VERSION 5.7 ;
BUSBITCHARS "[]" ;
DIVIDERCHAR "/" ;

UNITS
  DATABASE MICRONS 2000 ;
END UNITS

# Site definition
SITE core7
  CLASS CORE ;
  SIZE 0.38 BY 2.8 ;
END core7

# Metal layers for routing
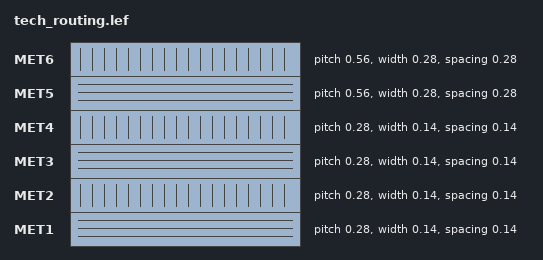
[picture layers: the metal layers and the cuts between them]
LAYER MET1
  TYPE ROUTING ;
  DIRECTION HORIZONTAL ;
  PITCH 0.28 ;
  WIDTH 0.14 ;
  SPACING 0.14 ;
  RESISTANCE RPERSQ 0.08 ;
  CAPACITANCE CPERSQDIST 0.00015 ;
END MET1

LAYER MET2
  TYPE ROUTING ;
  DIRECTION VERTICAL ;
  PITCH 0.28 ;
  WIDTH 0.14 ;
  SPACING 0.14 ;
  RESISTANCE RPERSQ 0.08 ;
  CAPACITANCE CPERSQDIST 0.00015 ;
END MET2

LAYER MET3
  TYPE ROUTING ;
  DIRECTION HORIZONTAL ;
  PITCH 0.28 ;
  WIDTH 0.14 ;
  SPACING 0.14 ;
  RESISTANCE RPERSQ 0.08 ;
  CAPACITANCE CPERSQDIST 0.00015 ;
END MET3

LAYER MET4
  TYPE ROUTING ;
  DIRECTION VERTICAL ;
  PITCH 0.28 ;
  WIDTH 0.14 ;
  SPACING 0.14 ;
  RESISTANCE RPERSQ 0.08 ;
  CAPACITANCE CPERSQDIST 0.00015 ;
END MET4

LAYER MET5
  TYPE ROUTING ;
  DIRECTION HORIZONTAL ;
  PITCH 0.56 ;
  WIDTH 0.28 ;
  SPACING 0.28 ;
  RESISTANCE RPERSQ 0.04 ;
  CAPACITANCE CPERSQDIST 0.00012 ;
END MET5

LAYER MET6
  TYPE ROUTING ;
  DIRECTION VERTICAL ;
  PITCH 0.56 ;
  WIDTH 0.28 ;
  SPACING 0.28 ;
  RESISTANCE RPERSQ 0.04 ;
  CAPACITANCE CPERSQDIST 0.00012 ;
END MET6

# Via definitions
VIA VIA12 DEFAULT
  LAYER MET1 ;
    RECT -0.07 -0.07 0.07 0.07 ;
  LAYER VIA1 ;
    RECT -0.065 -0.065 0.065 0.065 ;
  LAYER MET2 ;
    RECT -0.07 -0.07 0.07 0.07 ;
END VIA12

VIA VIA23 DEFAULT
  LAYER MET2 ;
    RECT -0.07 -0.07 0.07 0.07 ;
  LAYER VIA2 ;
    RECT -0.065 -0.065 0.065 0.065 ;
  LAYER MET3 ;
    RECT -0.07 -0.07 0.07 0.07 ;
END VIA23

VIA VIA34 DEFAULT
  LAYER MET3 ;
    RECT -0.07 -0.07 0.07 0.07 ;
  LAYER VIA3 ;
    RECT -0.065 -0.065 0.065 0.065 ;
  LAYER MET4 ;
    RECT -0.07 -0.07 0.07 0.07 ;
END VIA34

VIA VIA45 DEFAULT
  LAYER MET4 ;
    RECT -0.14 -0.14 0.14 0.14 ;
  LAYER VIA4 ;
    RECT -0.13 -0.13 0.13 0.13 ;
  LAYER MET5 ;
    RECT -0.14 -0.14 0.14 0.14 ;
END VIA45

VIA VIA56 DEFAULT
  LAYER MET5 ;
    RECT -0.14 -0.14 0.14 0.14 ;
  LAYER VIA5 ;
    RECT -0.13 -0.13 0.13 0.13 ;
  LAYER MET6 ;
    RECT -0.14 -0.14 0.14 0.14 ;
END VIA56

END LIBRARY
